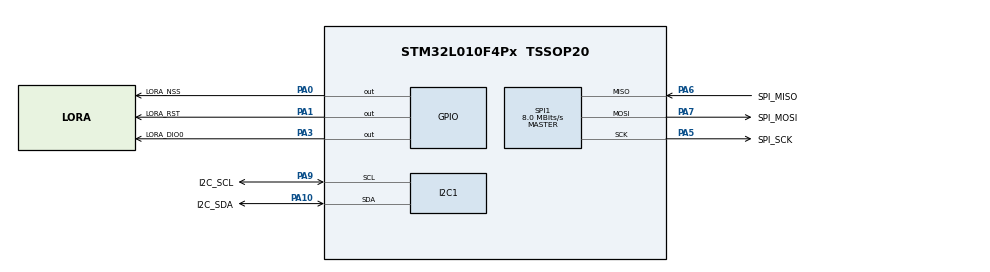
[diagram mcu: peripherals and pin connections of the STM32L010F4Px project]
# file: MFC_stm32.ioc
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I2C1.Speed=10
I2C1.Timing=0x40003EFF
Mcu.Family=STM32L0
Mcu.Name=STM32L010F4Px
Mcu.Package=TSSOP20
PA0-CK_IN.GPIO_Label=LORA_NSS
PA0-CK_IN.Signal=GPIO_Output
PA1.GPIO_Label=LORA_RST
PA1.Signal=GPIO_Output
PA10.GPIO_Label=I2C_SDA
PA10.GPIO_Pu=GPIO_PULLUP
PA10.Mode=I2C
PA10.Signal=I2C1_SDA
PA13.Mode=Serial_Wire
PA13.Signal=SYS_SWDIO
PA14.Mode=Serial_Wire
PA14.Signal=SYS_SWCLK
PA3.GPIO_Label=LORA_DIO0
PA3.Signal=GPIO_Output
PA5.GPIO_Label=SPI_SCK
PA5.Mode=Full_Duplex_Master
PA5.Signal=SPI1_SCK
PA6.GPIO_Label=SPI_MISO
PA6.Mode=Full_Duplex_Master
PA6.Signal=SPI1_MISO
PA7.GPIO_Label=SPI_MOSI
PA7.Mode=Full_Duplex_Master
PA7.Signal=SPI1_MOSI
PA9.GPIO_Label=I2C_SCL
PA9.GPIO_Pu=GPIO_PULLUP
PA9.Mode=I2C
PA9.Signal=I2C1_SCL
PC14-OSC32_IN.Mode=LSE-External-Oscillator
PC14-OSC32_IN.Signal=RCC_OSC32_IN
PC15-OSC32_OUT.Mode=LSE-External-Oscillator
PC15-OSC32_OUT.Signal=RCC_OSC32_OUT
ProjectManager.HeapSize=0x200
ProjectManager.StackSize=0x400
ProjectManager.TargetToolchain=EWARM V8.32
RCC.AHBFreq_Value=16000000
RCC.APB1Freq_Value=16000000
RCC.APB1TimFreq_Value=16000000
RCC.APB2Freq_Value=16000000
RCC.APB2TimFreq_Value=16000000
RCC.HCLKFreq_Value=16000000
RCC.HSE_VALUE=8000000
RCC.HSI16_VALUE=16000000
RCC.HSI_VALUE=16000000
RCC.MSI_VALUE=2097000
RCC.PLLDIV=RCC_PLLDIV_3
RCC.RTCClockSelection=RCC_RTCCLKSOURCE_LSE
RCC.RTCClockSelectionVirtual=RCC_RTCCLKSOURCE_LSE
RCC.SYSCLKFreq_VALUE=16000000
RCC.SYSCLKSource=RCC_SYSCLKSOURCE_PLLCLK
RCC.VCOOutputFreq_Value=48000000
SPI1.CalculateBaudRate=8.0 MBits/s
SPI1.Direction=SPI_DIRECTION_2LINES
SPI1.Mode=SPI_MODE_MASTER
SPI1.VirtualType=VM_MASTER
board=custom

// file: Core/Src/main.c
/* USER CODE BEGIN Header */
/**
  ******************************************************************************
  * @file           : main.c
  * @brief          : Main program body
  ******************************************************************************
  * @attention
  *
  * <h2><center>&copy; Copyright (c) 2021 STMicroelectronics.
  * All rights reserved.</center></h2>
  *
  * This software component is licensed by ST under BSD 3-Clause license,
  * the "License"; You may not use this file except in compliance with the
  * License. You may obtain a copy of the License at:
  *                        opensource.org/licenses/BSD-3-Clause
  *
  ******************************************************************************
  */
/* USER CODE END Header */
#include "main.h"

I2C_HandleTypeDef hi2c1;

SPI_HandleTypeDef hspi1;

void SystemClock_Config(void);
static void MX_GPIO_Init(void);
static void MX_I2C1_Init(void);
static void MX_SPI1_Init(void);

int main(void)
{

  /* MCU Configuration--------------------------------------------------------*/

  /* Reset of all peripherals, Initializes the Flash interface and the Systick. */
  HAL_Init();

  /* Configure the system clock */
  SystemClock_Config();

  /* Initialize all configured peripherals */
  MX_GPIO_Init();
  MX_I2C1_Init();
  MX_SPI1_Init();

  /* Infinite loop */
  while (1)
  {

  }
}

void SystemClock_Config(void)
{
  RCC_OscInitTypeDef RCC_OscInitStruct = {0};
  RCC_ClkInitTypeDef RCC_ClkInitStruct = {0};
  RCC_PeriphCLKInitTypeDef PeriphClkInit = {0};

  /** Configure the main internal regulator output voltage
  */
  __HAL_PWR_VOLTAGESCALING_CONFIG(PWR_REGULATOR_VOLTAGE_SCALE1);
  /** Initializes the RCC Oscillators according to the specified parameters
  * in the RCC_OscInitTypeDef structure.
  */
  RCC_OscInitStruct.OscillatorType = RCC_OSCILLATORTYPE_HSI;
  RCC_OscInitStruct.HSIState = RCC_HSI_ON;
  RCC_OscInitStruct.HSICalibrationValue = RCC_HSICALIBRATION_DEFAULT;
  RCC_OscInitStruct.PLL.PLLState = RCC_PLL_ON;
  RCC_OscInitStruct.PLL.PLLSource = RCC_PLLSOURCE_HSI;
  RCC_OscInitStruct.PLL.PLLMUL = RCC_PLLMUL_4;
  RCC_OscInitStruct.PLL.PLLDIV = RCC_PLLDIV_2;
  if (HAL_RCC_OscConfig(&RCC_OscInitStruct) != HAL_OK)
  {
    Error_Handler();
  }
  /** Initializes the CPU, AHB and APB buses clocks
  */
  RCC_ClkInitStruct.ClockType = RCC_CLOCKTYPE_HCLK|RCC_CLOCKTYPE_SYSCLK
                              |RCC_CLOCKTYPE_PCLK1|RCC_CLOCKTYPE_PCLK2;
  RCC_ClkInitStruct.SYSCLKSource = RCC_SYSCLKSOURCE_PLLCLK;
  RCC_ClkInitStruct.AHBCLKDivider = RCC_SYSCLK_DIV1;
  RCC_ClkInitStruct.APB1CLKDivider = RCC_HCLK_DIV1;
  RCC_ClkInitStruct.APB2CLKDivider = RCC_HCLK_DIV1;

  if (HAL_RCC_ClockConfig(&RCC_ClkInitStruct, FLASH_LATENCY_1) != HAL_OK)
  {
    Error_Handler();
  }
  PeriphClkInit.PeriphClockSelection = RCC_PERIPHCLK_I2C1;
  PeriphClkInit.I2c1ClockSelection = RCC_I2C1CLKSOURCE_PCLK1;
  if (HAL_RCCEx_PeriphCLKConfig(&PeriphClkInit) != HAL_OK)
  {
    Error_Handler();
  }
}

static void MX_I2C1_Init(void)
{

  hi2c1.Instance = I2C1;
  hi2c1.Init.Timing = 0x6010C7FF;
  hi2c1.Init.OwnAddress1 = 0;
  hi2c1.Init.AddressingMode = I2C_ADDRESSINGMODE_7BIT;
  hi2c1.Init.DualAddressMode = I2C_DUALADDRESS_DISABLE;
  hi2c1.Init.OwnAddress2 = 0;
  hi2c1.Init.OwnAddress2Masks = I2C_OA2_NOMASK;
  hi2c1.Init.GeneralCallMode = I2C_GENERALCALL_DISABLE;
  hi2c1.Init.NoStretchMode = I2C_NOSTRETCH_DISABLE;
  if (HAL_I2C_Init(&hi2c1) != HAL_OK)
  {
    Error_Handler();
  }
  /** Configure Analogue filter
  */
  if (HAL_I2CEx_ConfigAnalogFilter(&hi2c1, I2C_ANALOGFILTER_ENABLE) != HAL_OK)
  {
    Error_Handler();
  }
  /** Configure Digital filter
  */
  if (HAL_I2CEx_ConfigDigitalFilter(&hi2c1, 0) != HAL_OK)
  {
    Error_Handler();
  }

}

static void MX_SPI1_Init(void)
{

  /* SPI1 parameter configuration*/
  hspi1.Instance = SPI1;
  hspi1.Init.Mode = SPI_MODE_MASTER;
  hspi1.Init.Direction = SPI_DIRECTION_2LINES;
  hspi1.Init.DataSize = SPI_DATASIZE_8BIT;
  hspi1.Init.CLKPolarity = SPI_POLARITY_LOW;
  hspi1.Init.CLKPhase = SPI_PHASE_1EDGE;
  hspi1.Init.NSS = SPI_NSS_SOFT;
  hspi1.Init.BaudRatePrescaler = SPI_BAUDRATEPRESCALER_2;
  hspi1.Init.FirstBit = SPI_FIRSTBIT_MSB;
  hspi1.Init.TIMode = SPI_TIMODE_DISABLE;
  hspi1.Init.CRCCalculation = SPI_CRCCALCULATION_DISABLE;
  hspi1.Init.CRCPolynomial = 7;
  if (HAL_SPI_Init(&hspi1) != HAL_OK)
  {
    Error_Handler();
  }

}

static void MX_GPIO_Init(void)
{
  GPIO_InitTypeDef GPIO_InitStruct = {0};

  /* GPIO Ports Clock Enable */
  __HAL_RCC_GPIOC_CLK_ENABLE();
  __HAL_RCC_GPIOA_CLK_ENABLE();
  __HAL_RCC_GPIOB_CLK_ENABLE();

  /*Configure GPIO pin Output Level */
  HAL_GPIO_WritePin(GPIOA, LORA_NSS_Pin|LORA_RST_Pin|LORA_DIO0_Pin, GPIO_PIN_RESET);

  /*Configure GPIO pin Output Level */
  HAL_GPIO_WritePin(LOAD_SW_GPIO_Port, LOAD_SW_Pin, GPIO_PIN_RESET);

  /*Configure GPIO pins : LORA_NSS_Pin LORA_RST_Pin LORA_DIO0_Pin */
  GPIO_InitStruct.Pin = LORA_NSS_Pin|LORA_RST_Pin|LORA_DIO0_Pin;
  GPIO_InitStruct.Mode = GPIO_MODE_OUTPUT_PP;
  GPIO_InitStruct.Pull = GPIO_NOPULL;
  GPIO_InitStruct.Speed = GPIO_SPEED_FREQ_LOW;
  HAL_GPIO_Init(GPIOA, &GPIO_InitStruct);

  /*Configure GPIO pin : POWER_GOOD_Pin */
  GPIO_InitStruct.Pin = POWER_GOOD_Pin;
  GPIO_InitStruct.Mode = GPIO_MODE_INPUT;
  GPIO_InitStruct.Pull = GPIO_NOPULL;
  HAL_GPIO_Init(POWER_GOOD_GPIO_Port, &GPIO_InitStruct);

  /*Configure GPIO pin : LOAD_SW_Pin */
  GPIO_InitStruct.Pin = LOAD_SW_Pin;
  GPIO_InitStruct.Mode = GPIO_MODE_OUTPUT_PP;
  GPIO_InitStruct.Pull = GPIO_NOPULL;
  GPIO_InitStruct.Speed = GPIO_SPEED_FREQ_LOW;
  HAL_GPIO_Init(LOAD_SW_GPIO_Port, &GPIO_InitStruct);

}

void Error_Handler(void)
{
  __disable_irq();
  while (1)
  {
  }
}

/************************ (C) COPYRIGHT STMicroelectronics *****END OF FILE****/
